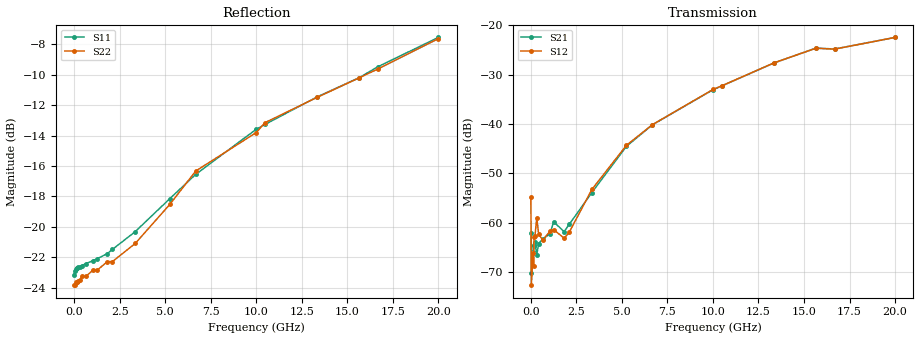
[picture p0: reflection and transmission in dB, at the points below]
!  2-Port S-parameters saved by WinCal
! VAR MeasName=S-Parameters (CALIBRATED_DATA) read from VNA (N5244A)
! VAR MeasDate=11/27/2015 2:03:44 PM
! VAR NAME=A150205IS0
! VAR FILENAME=A150205IS0.S2P
! VAR DATE=11/27/2015 2:03:44 PM
! VAR PHYS_PORTS=1,2
# Hz S DB R 50
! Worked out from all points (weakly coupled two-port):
!   801 points, 10 MHz to 20 GHz, reference 50 ohm
!   highest |S21| = -22.47 dB at 20 GHz (marker M1); lowest = -70.2 dB at 34.99 MHz (marker M2)
!   lowest |S11| = -23.2 dB at 10 MHz (marker M3), VSWR 1.15, Z = 43.5 - j0.0054 ohm
!   |S11| at or under -10 dB: start of sweep to 16.01 GHz
!   |S22| runs from -23.8 to -7.6 dB; largest |S21 - S12| = 0.0019
!   S11 on the Smith chart (normalised r, x): 10 MHz: 0.87, -0.00; 10.48 GHz: 0.71, -0.24; 20 GHz: 0.44, -0.25
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1e7  -23.18 -179.9  -62.02 40.1  -54.71 125.0  -23.84 -178.5
3.49875e7  -22.92 -179.0  -70.20 64.6  -72.59 -105.5  -23.81 -179.3
1.349375e8  -22.79 -177.2  -65.80 79.1  -66.14 39.9  -23.63 -176.7
1.59925e8  -22.73 -177.2  -64.45 99.2  -68.65 57.0  -23.62 -176.7
1.849125e8  -22.73 -176.3  -64.76 51.3  -62.92 56.2  -23.64 -176.5
2.348875e8  -22.68 -176.4  -63.95 98.3  -62.64 65.6  -23.58 -176.0
3.348375e8  -22.64 -174.6  -66.49 63.4  -58.92 60.0  -23.48 -174.8
4.347875e8  -22.55 -174.0  -64.18 37.0  -62.26 52.2  -23.27 -172.8
6.59675e8  -22.42 -171.3  -63.28 48.3  -63.48 37.5  -23.26 -169.8
1.059475e9  -22.22 -167.1  -62.22 50.8  -61.69 35.8  -22.83 -165.7
1.259375e9  -22.11 -165.2  -59.77 52.3  -61.35 55.4  -22.87 -162.2
1.834088e9  -21.76 -159.4  -61.78 77.5  -63.10 65.8  -22.29 -156.0
2.10895e9  -21.49 -156.4  -60.32 103.0  -61.94 89.4  -22.29 -154.9
3.358325e9  -20.32 -146.5  -53.86 129.5  -53.23 133.3  -21.10 -145.3
5.257375e9  -18.15 -136.6  -44.50 142.8  -44.29 145.4  -18.53 -136.8
6.681662e9  -16.55 -133.5  -40.16 143.2  -40.12 140.0  -16.33 -132.3
1.0005e10  -13.58 -133.2  -33.06 133.0  -33.01 133.2  -13.80 -131.0
1.047976e10  -13.27 -133.2  -32.31 130.9  -32.28 129.8  -13.15 -131.0
1.335332e10  -11.45 -136.1  -27.65 124.0  -27.62 123.6  -11.48 -136.3
1.565218e10  -10.19 -138.7  -24.63 107.6  -24.67 107.6  -10.20 -139.1
1.667666e10  -9.47 -138.5  -24.82 100.7  -24.85 100.9  -9.62 -139.4
2e10  -7.54 -146.5  -22.47 96.3  -22.48 96.2  -7.62 -146.6
